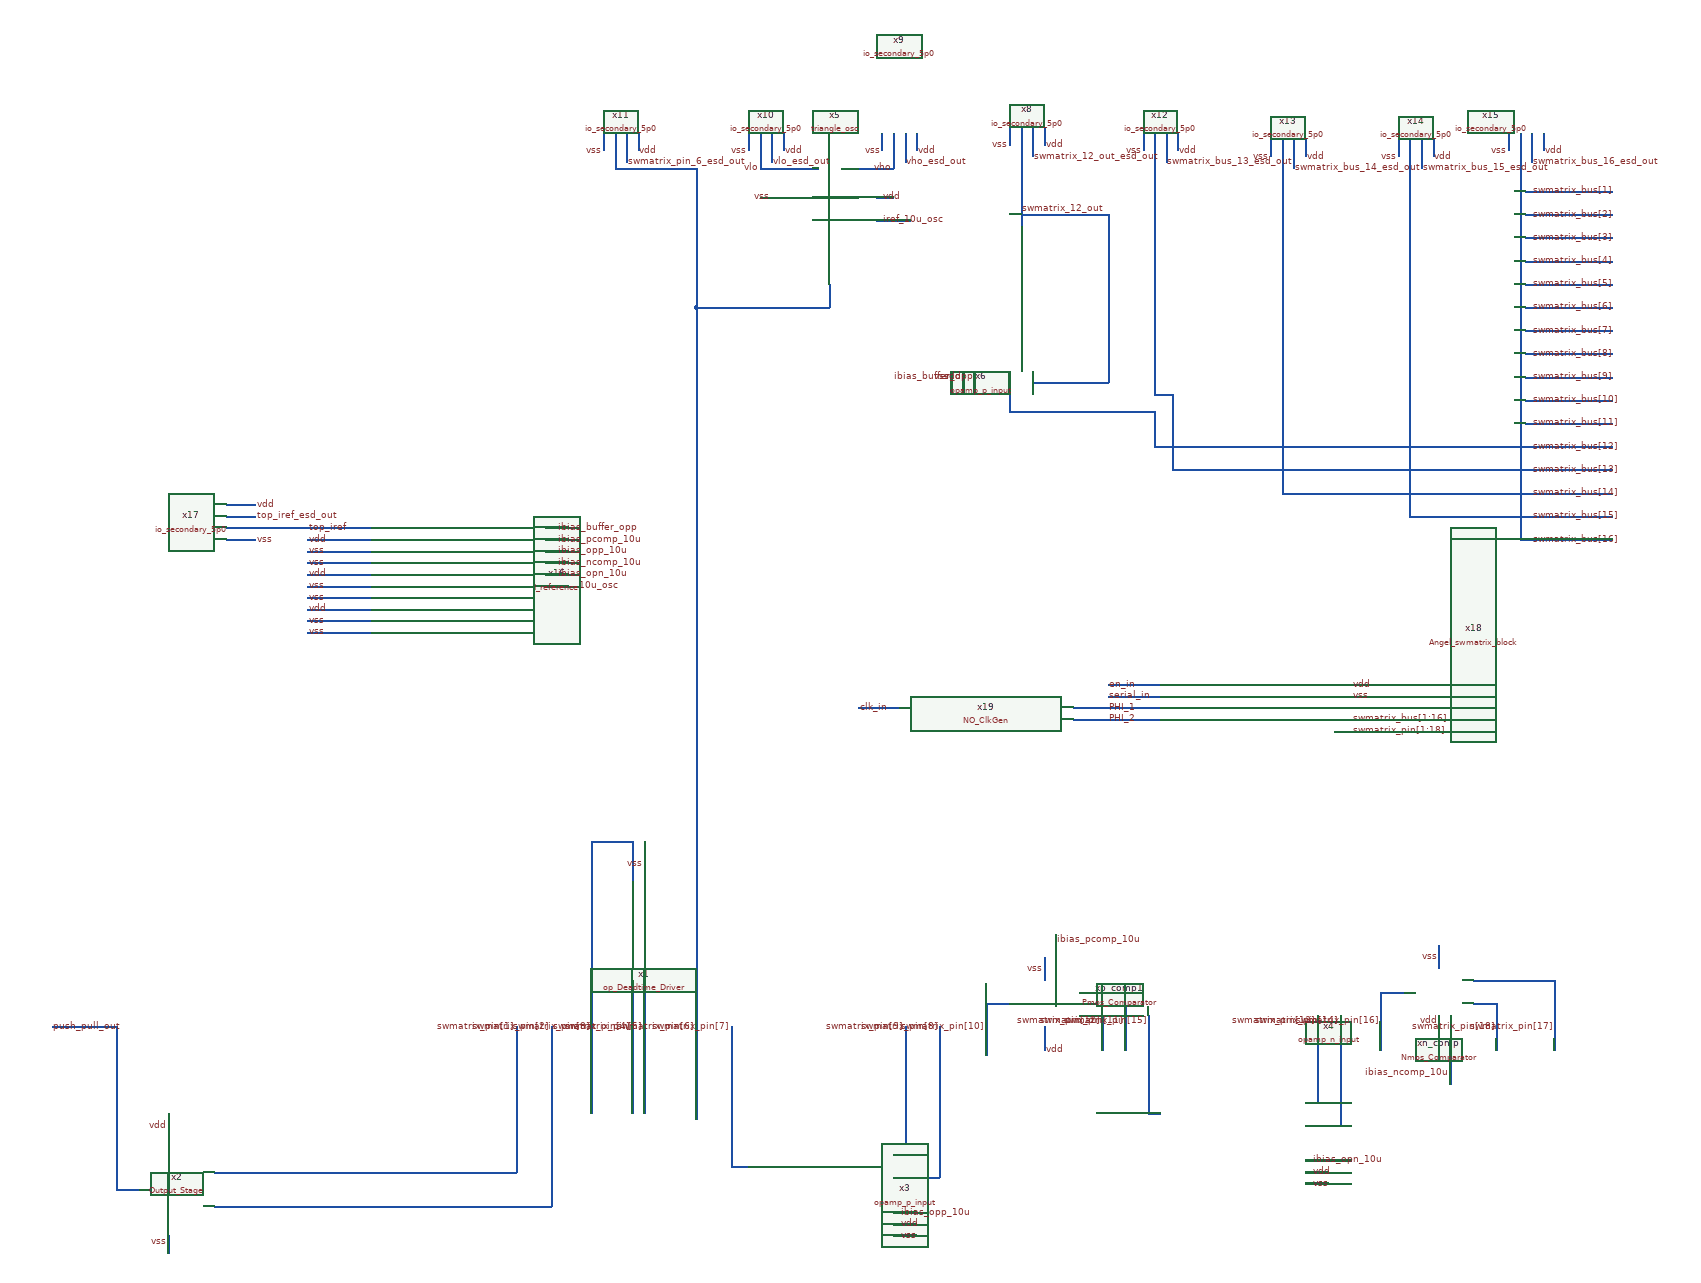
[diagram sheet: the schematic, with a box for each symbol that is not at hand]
v {xschem version=3.4.7 file_version=1.2}
G {}
K {}
V {}
S {}
E {}
N 1850 -2800 1900 -2800 {lab=vho}
N 1900 -2860 1900 -2800 {lab=vho}
N 1670 -2860 1670 -2800 {lab=vlo}
N 1420 -2860 1420 -2840 {lab=swmatrix_pin[6]}
N 2570 -2850 2570 -2820 {lab=swmatrix_bus[14]}
N 2790 -2850 2790 -2820 {lab=swmatrix_bus[15]}
N 2120 -2750 2120 -2700 {lab=swmatrix_12_out}
N 2140 -2450 2140 -2430 {lab=swmatrix_12_out}
N 2140 -2430 2270 -2430 {lab=swmatrix_12_out}
N 2270 -2710 2270 -2430 {lab=swmatrix_12_out}
N 2120 -2720 2270 -2720 {lab=swmatrix_12_out}
N 2270 -2720 2270 -2710 {lab=swmatrix_12_out}
N 650 -1170 650 -1120 {lab=vdd}
N 1670 -2750 1710 -2750 {lab=vss}
N 1870 -2750 1900 -2750 {lab=vdd}
N 1880 -2710 1930 -2710 {lab=iref_10u_osc}
N 1870 -2710 1880 -2710 {lab=iref_10u_osc}
N 1790 -2600 1790 -2560 {lab=swmatrix_pin[6]}
N 2000 -2450 2000 -2410 {lab=vss}
N 2020 -2450 2020 -2410 {lab=vdd}
N 2040 -2450 2040 -2410 {lab=ibias_buffer_opp}
N 2100 -2450 2100 -2390 {lab=swmatrix_bus[12]}
N 1900 -960 1940 -960 {lab=vss}
N 1900 -980 1940 -980 {lab=vdd}
N 1900 -1000 1940 -1000 {lab=ibias_opp_10u}
N 2610 -1050 2650 -1050 {lab=vss}
N 2610 -1070 2650 -1070 {lab=vdd}
N 2610 -1090 2650 -1090 {lab=ibias_opn_10u}
N 1900 -1100 1920 -1100 {lab=swmatrix_pin[9]}
N 1920 -1220 1920 -1100 {lab=swmatrix_pin[9]}
N 1980 -1320 1980 -1060 {lab=swmatrix_pin[8]}
N 1920 -1320 1920 -1220 {lab=swmatrix_pin[9]}
N 1620 -1320 1620 -1080 {lab=swmatrix_pin[7]}
N 2610 -1190 2630 -1190 {lab=swmatrix_pin[13]}
N 2630 -1310 2630 -1190 {lab=swmatrix_pin[13]}
N 2610 -1150 2650 -1150 {lab=swmatrix_pin[14]}
N 2650 -1090 2690 -1090 {lab=ibias_opn_10u}
N 2160 -1440 2160 -1400 {lab=vss}
N 2160 -1320 2160 -1280 {lab=vdd}
N 2160 -1440 2160 -1400 {lab=vss}
N 2160 -1320 2160 -1280 {lab=vdd}
N 2180 -1440 2180 -1400 {lab=ibias_pcomp_10u}
N 2180 -1480 2180 -1440 {lab=ibias_pcomp_10u}
N 2060 -1360 2100 -1360 {lab=swmatrix_pin[10]}
N 2220 -1340 2260 -1340 {lab=swmatrix_pin[12]}
N 2900 -1360 2940 -1360 {lab=swmatrix_pin[18]}
N 2900 -1400 3040 -1400 {lab=swmatrix_pin[17]}
N 2740 -1380 2780 -1380 {lab=swmatrix_pin[16]}
N 2840 -1460 2840 -1420 {lab=vss}
N 2840 -1460 2840 -1420 {lab=vss}
N 2860 -1340 2860 -1300 {lab=ibias_ncomp_10u}
N 1470 -1640 1470 -1570 {lab=vss}
N 1450 -1640 1450 -1570 {lab=swmatrix_pin[3]}
N 1380 -1640 1380 -1300 {lab=swmatrix_pin[3]}
N 1450 -1400 1450 -1300 {lab=swmatrix_pin[4]}
N 1670 -2800 1770 -2800 {lab=vlo}
N 1810 -2800 1850 -2800 {lab=vho}
N 1450 -1300 1450 -1170 {lab=swmatrix_pin[4]}
N 1380 -1300 1380 -1170 {lab=swmatrix_pin[3]}
N 1470 -1400 1470 -1170 {lab=swmatrix_pin[5]}
N 650 -960 650 -930 {lab=vss}
N 730 -1070 1250 -1070 {lab=swmatrix_pin[1]}
N 1250 -1170 1250 -1070 {lab=swmatrix_pin[1]}
N 730 -1010 1310 -1010 {lab=swmatrix_pin[2]}
N 1310 -1160 1310 -1010 {lab=swmatrix_pin[2]}
N 1310 -1170 1310 -1160 {lab=swmatrix_pin[2]}
N 1250 -1320 1250 -1170 {lab=swmatrix_pin[1]}
N 1310 -1320 1310 -1170 {lab=swmatrix_pin[2]}
N 2060 -1360 2060 -1300 {lab=swmatrix_pin[10]}
N 2260 -1340 2260 -1280 {lab=swmatrix_pin[12]}
N 2300 -1380 2300 -1280 {lab=swmatrix_pin[11]}
N 2740 -1380 2740 -1280 {lab=swmatrix_pin[16]}
N 2940 -1360 2940 -1280 {lab=swmatrix_pin[18]}
N 3040 -1400 3040 -1280 {lab=swmatrix_pin[17]}
N 2860 -1300 2860 -1220 {lab=ibias_ncomp_10u}
N 2670 -1310 2670 -1150 {lab=swmatrix_pin[14]}
N 2340 -1340 2340 -1170 {lab=swmatrix_pin[15]}
N 2630 -1340 2630 -1310 {lab=swmatrix_pin[13]}
N 2670 -1340 2670 -1310 {lab=swmatrix_pin[14]}
N 2840 -1340 2840 -1310 {lab=vdd}
N 1560 -2280 1560 -1160 {lab=swmatrix_pin[6]}
N 1380 -1640 1450 -1640 {lab=swmatrix_pin[3]}
N 1620 -1080 1650 -1080 {lab=swmatrix_pin[7]}
N 1900 -1060 1980 -1060 {lab=swmatrix_pin[8]}
N 2060 -1300 2060 -1270 {lab=swmatrix_pin[10]}
N 2650 -1150 2670 -1150 {lab=swmatrix_pin[14]}
N 2340 -1170 2360 -1170 {lab=swmatrix_pin[15]}
N 2220 -1380 2300 -1380 {lab=swmatrix_pin[11]}
N 2120 -2760 2120 -2750 {lab=swmatrix_12_out}
N 2990 -2760 3140 -2760 {lab=swmatrix_bus[1]}
N 2790 -2820 2790 -2720 {lab=swmatrix_bus[15]}
N 2570 -2820 2570 -2680 {lab=swmatrix_bus[14]}
N 2990 -2600 3140 -2600 {lab=swmatrix_bus[5]}
N 2990 -2560 3140 -2560 {lab=swmatrix_bus[6]}
N 2990 -2520 3140 -2520 {lab=swmatrix_bus[7]}
N 2990 -2480 3140 -2480 {lab=swmatrix_bus[8]}
N 2990 -2440 3140 -2440 {lab=swmatrix_bus[9]}
N 2990 -2400 3140 -2400 {lab=swmatrix_bus[10]}
N 2990 -2360 3140 -2360 {lab=swmatrix_bus[11]}
N 2990 -2320 3140 -2320 {lab=swmatrix_bus[12]}
N 2100 -2380 2350 -2380 {lab=swmatrix_bus[12]}
N 2100 -2390 2100 -2380 {lab=swmatrix_bus[12]}
N 2990 -2280 3140 -2280 {lab=swmatrix_bus[13]}
N 2990 -2240 3140 -2240 {lab=swmatrix_bus[14]}
N 2990 -2200 3140 -2200 {lab=swmatrix_bus[15]}
N 2990 -2160 3140 -2160 {lab=swmatrix_bus[16]}
N 1560 -2560 1560 -2280 {lab=swmatrix_pin[6]}
N 560 -1040 600 -1040 {lab=push_pull_out}
N 560 -1320 560 -1040 {lab=push_pull_out}
N 450 -1320 560 -1320 {lab=push_pull_out}
N 1560 -2560 1790 -2560 {lab=swmatrix_pin[6]}
N 1560 -2800 1560 -2560 {lab=swmatrix_pin[6]}
N 1420 -2800 1550 -2800 {lab=swmatrix_pin[6]}
N 1420 -2840 1420 -2800 {lab=swmatrix_pin[6]}
N 1550 -2800 1560 -2800 {lab=swmatrix_pin[6]}
N 2350 -2860 2350 -2640 {lab=swmatrix_bus[13]}
N 2120 -2870 2120 -2760 {lab=swmatrix_12_out}
N 3020 -2860 3020 -2830 {lab=vdd}
N 2830 -2850 2830 -2820 {lab=vdd}
N 2610 -2850 2610 -2820 {lab=vdd}
N 2390 -2860 2390 -2830 {lab=vdd}
N 2160 -2870 2160 -2840 {lab=vdd}
N 1940 -2860 1940 -2840 {lab=vdd}
N 1940 -2840 1940 -2830 {lab=vdd}
N 1710 -2860 1710 -2830 {lab=vdd}
N 1460 -2860 1460 -2830 {lab=vdd}
N 3000 -2860 3000 -2830 {lab=swmatrix_bus_16_esd_out}
N 2810 -2850 2810 -2820 {lab=swmatrix_bus_15_esd_out}
N 2590 -2850 2590 -2820 {lab=swmatrix_bus_14_esd_out}
N 2770 -2850 2770 -2820 {lab=vss}
N 2550 -2850 2550 -2820 {lab=vss}
N 2960 -2860 2960 -2830 {lab=vss}
N 2370 -2860 2370 -2830 {lab=swmatrix_bus_13_esd_out}
N 2330 -2860 2330 -2830 {lab=vss}
N 2140 -2870 2140 -2840 {lab=swmatrix_12_out_esd_out}
N 2100 -2870 2100 -2840 {lab=vss}
N 1920 -2860 1920 -2830 {lab=vho_esd_out}
N 1880 -2860 1880 -2830 {lab=vss}
N 1690 -2860 1690 -2830 {lab=vlo_esd_out}
N 1650 -2860 1650 -2830 {lab=vss}
N 1440 -2860 1440 -2830 {lab=swmatrix_pin_6_esd_out}
N 1400 -2860 1400 -2830 {lab=vss}
N 2810 -2820 2810 -2800 {lab=swmatrix_bus_15_esd_out}
N 2590 -2820 2590 -2800 {lab=swmatrix_bus_14_esd_out}
N 2370 -2830 2370 -2810 {lab=swmatrix_bus_13_esd_out}
N 2140 -2840 2140 -2820 {lab=swmatrix_12_out_esd_out}
N 1920 -2830 1920 -2810 {lab=vho_esd_out}
N 1690 -2830 1690 -2810 {lab=vlo_esd_out}
N 1440 -2830 1440 -2810 {lab=swmatrix_pin_6_esd_out}
N 2350 -2320 2990 -2320 {lab=swmatrix_bus[12]}
N 2350 -2380 2350 -2320 {lab=swmatrix_bus[12]}
N 2990 -2640 3140 -2640 {lab=swmatrix_bus[4]}
N 2350 -2640 2350 -2410 {lab=swmatrix_bus[13]}
N 2350 -2410 2380 -2410 {lab=swmatrix_bus[13]}
N 2380 -2410 2380 -2280 {lab=swmatrix_bus[13]}
N 2380 -2280 2990 -2280 {lab=swmatrix_bus[13]}
N 2570 -2680 2570 -2240 {lab=swmatrix_bus[14]}
N 2570 -2240 2990 -2240 {lab=swmatrix_bus[14]}
N 2790 -2720 2790 -2200 {lab=swmatrix_bus[15]}
N 2790 -2200 2990 -2200 {lab=swmatrix_bus[15]}
N 2990 -2720 3140 -2720 {lab=swmatrix_bus[2]}
N 2990 -2680 3140 -2680 {lab=swmatrix_bus[3]}
N 3000 -2830 3000 -2810 {lab=swmatrix_bus_16_esd_out}
N 2980 -2860 2980 -2160 {lab=swmatrix_bus[16]}
N 2980 -2160 2990 -2160 {lab=swmatrix_bus[16]}
N 960 -2180 1000 -2180 {lab=top_iref}
N 890 -2180 960 -2180 {lab=top_iref}
N 890 -2160 1000 -2160 {lab=vdd}
N 890 -2140 1000 -2140 {lab=vss}
N 890 -2120 1000 -2120 {lab=vss}
N 890 -2100 1000 -2100 {lab=vdd}
N 890 -2080 1000 -2080 {lab=vss}
N 890 -2060 1000 -2060 {lab=vss}
N 890 -2040 1000 -2040 {lab=vdd}
N 890 -2020 1000 -2020 {lab=vss}
N 890 -2000 1000 -2000 {lab=vss}
N 1300 -2180 1340 -2180 {lab=ibias_buffer_opp}
N 1300 -2160 1340 -2160 {lab=ibias_pcomp_10u}
N 1300 -2140 1340 -2140 {lab=ibias_opp_10u}
N 1300 -2120 1340 -2120 {lab=ibias_ncomp_10u}
N 1300 -2100 1340 -2100 {lab=ibias_opn_10u}
N 1300 -2080 1340 -2080 {lab=iref_10u_osc}
N 750 -2180 890 -2180 {lab=top_iref}
N 750 -2200 800 -2200 {lab=top_iref_esd_out}
N 750 -2220 800 -2220 {lab=vdd}
N 750 -2160 800 -2160 {lab=vss}
N 2660 -1870 2690 -1870 {lab=#net1}
N 2660 -1910 2690 -1910 {lab=vdd}
N 2660 -1890 2690 -1890 {lab=vss}
N 2660 -1850 2690 -1850 {lab=swmatrix_bus[1:16]}
N 2660 -1830 2690 -1830 {lab=swmatrix_pin[1:18]}
N 2210 -1870 2360 -1870 {lab=PHI_1}
N 2210 -1850 2360 -1850 {lab=PHI_2}
N 2270 -1890 2360 -1890 {lab=serial_in}
N 2270 -1910 2360 -1910 {lab=en_in}
N 1840 -1870 1910 -1870 {lab=clk_in}
C {title.sym} 70 30 0 0 {name=l1 author=", X.J. Lee, Christopher O Amankwaa"}
C {libs/core_analog/Comparator/Nmos_Comparator.sym} 2880 -1340 2 0 {name=xn_comp}
C {libs/core_analog/op_Deadtime_Driver/op_Deadtime_Driver.sym} 1460 -1420 3 1 {name=x1}
C {libs/core_analog/Output_Stage/Output_Stage.sym} 680 -1040 0 1 {name=x2}
C {libs/core_analog/opamp/opamp_p_input.sym} 1880 -1170 0 1 {name=x3}
C {libs/core_analog/opamp/opamp_n_input.sym} 2590 -1260 0 1 {name=x4}
C {libs/core_analog/oscillator/triangle_osc.sym} 1850 -2780 1 0 {name=x5}
C {libs/core_analog/opamp/opamp_p_input.sym} 2210 -2470 1 1 {name=x6}
C {lab_wire.sym} 1900 -2800 0 0 {name=p5 sig_type=std_logic lab=vho}
C {lab_wire.sym} 1670 -2800 0 0 {name=p6 sig_type=std_logic lab=vlo}
C {lab_wire.sym} 450 -1320 0 1 {name=p13 sig_type=std_logic lab=push_pull_out}
C {lab_wire.sym} 3000 -2640 0 1 {name=p56 sig_type=std_logic lab=swmatrix_bus[4]}
C {lab_wire.sym} 3000 -2600 0 1 {name=p59 sig_type=std_logic lab=swmatrix_bus[5]}
C {lab_wire.sym} 3000 -2680 0 1 {name=p60 sig_type=std_logic lab=swmatrix_bus[3]}
C {lab_wire.sym} 3000 -2720 0 1 {name=p61 sig_type=std_logic lab=swmatrix_bus[2]}
C {lab_wire.sym} 3000 -2760 0 1 {name=p62 sig_type=std_logic lab=swmatrix_bus[1]}
C {lab_wire.sym} 650 -1150 0 0 {name=p47 sig_type=std_logic lab=vdd}
C {lab_wire.sym} 1690 -2750 0 0 {name=p64 sig_type=std_logic lab=vss}
C {lab_wire.sym} 1880 -2750 0 1 {name=p65 sig_type=std_logic lab=vdd}
C {lab_wire.sym} 1880 -2710 0 1 {name=p66 sig_type=std_logic lab=iref_10u_osc}
C {lab_wire.sym} 2020 -2440 3 0 {name=p67 sig_type=std_logic lab=vdd}
C {lab_wire.sym} 2000 -2440 3 0 {name=p68 sig_type=std_logic lab=vss}
C {lab_wire.sym} 1910 -980 2 0 {name=p70 sig_type=std_logic lab=vdd}
C {lab_wire.sym} 1910 -960 2 0 {name=p71 sig_type=std_logic lab=vss}
C {lab_wire.sym} 1910 -1000 0 1 {name=p72 sig_type=std_logic lab=ibias_opp_10u}
C {lab_wire.sym} 2620 -1070 2 0 {name=p73 sig_type=std_logic lab=vdd}
C {lab_wire.sym} 2620 -1050 2 0 {name=p74 sig_type=std_logic lab=vss}
C {lab_wire.sym} 2620 -1090 0 1 {name=p75 sig_type=std_logic lab=ibias_opn_10u}
C {lab_wire.sym} 2160 -1280 0 1 {name=p76 sig_type=std_logic lab=vdd}
C {lab_wire.sym} 2180 -1470 2 0 {name=p78 sig_type=std_logic lab=ibias_pcomp_10u}
C {libs/core_analog/Comparator/Pmos_Comparator.sym} 2200 -1320 2 0 {name=xp_comp1}
C {lab_wire.sym} 2160 -1420 0 0 {name=p80 sig_type=std_logic lab=vss}
C {lab_wire.sym} 2840 -1440 0 0 {name=p82 sig_type=std_logic lab=vss}
C {lab_wire.sym} 2840 -1330 2 1 {name=p83 sig_type=std_logic lab=vdd}
C {lab_wire.sym} 2860 -1240 2 1 {name=p85 sig_type=std_logic lab=ibias_ncomp_10u}
C {lab_wire.sym} 1470 -1600 1 0 {name=p86 sig_type=std_logic lab=vss}
C {lab_wire.sym} 2630 -1330 1 1 {name=p94 sig_type=std_logic lab=swmatrix_pin[13]}
C {lab_wire.sym} 3040 -1320 1 1 {name=p101 sig_type=std_logic lab=swmatrix_pin[17]
}
C {lab_wire.sym} 650 -950 3 0 {name=p102 sig_type=std_logic lab=vss}
C {lab_wire.sym} 2120 -2730 0 1 {name=p77 sig_type=std_logic lab=swmatrix_12_out}
C {lab_wire.sym} 3000 -2560 0 1 {name=p81 sig_type=std_logic lab=swmatrix_bus[6]}
C {lab_wire.sym} 3000 -2400 0 1 {name=p84 sig_type=std_logic lab=swmatrix_bus[10]}
C {lab_wire.sym} 3000 -2360 0 1 {name=p105 sig_type=std_logic lab=swmatrix_bus[11]}
C {lab_wire.sym} 3000 -2440 0 1 {name=p106 sig_type=std_logic lab=swmatrix_bus[9]}
C {lab_wire.sym} 3000 -2480 0 1 {name=p107 sig_type=std_logic lab=swmatrix_bus[8]}
C {lab_wire.sym} 3000 -2520 0 1 {name=p108 sig_type=std_logic lab=swmatrix_bus[7]}
C {lab_wire.sym} 3000 -2320 0 1 {name=p109 sig_type=std_logic lab=swmatrix_bus[12]}
C {lab_wire.sym} 3000 -2240 0 1 {name=p110 sig_type=std_logic lab=swmatrix_bus[14]}
C {lab_wire.sym} 3000 -2200 0 1 {name=p111 sig_type=std_logic lab=swmatrix_bus[15]}
C {lab_wire.sym} 3000 -2280 0 1 {name=p112 sig_type=std_logic lab=swmatrix_bus[13]}
C {lab_wire.sym} 3000 -2160 0 1 {name=p113 sig_type=std_logic lab=swmatrix_bus[16]}
C {lab_wire.sym} 890 -2000 0 1 {name=p115 sig_type=std_logic lab=vss}
C {lab_wire.sym} 2040 -2440 3 0 {name=p119 sig_type=std_logic lab=ibias_buffer_opp}
C {lab_wire.sym} 1320 -2080 0 1 {name=p132 sig_type=std_logic lab=iref_10u_osc}
C {lab_wire.sym} 2940 -1320 1 1 {name=p100 sig_type=std_logic lab=swmatrix_pin[18]
}
C {lab_wire.sym} 2740 -1330 1 1 {name=p99 sig_type=std_logic lab=swmatrix_pin[16]
}
C {lab_wire.sym} 2670 -1330 1 1 {name=p95 sig_type=std_logic lab=swmatrix_pin[14]
}
C {lab_wire.sym} 2340 -1330 1 1 {name=p93 sig_type=std_logic lab=swmatrix_pin[15]}
C {lab_wire.sym} 2300 -1330 1 1 {name=p97 sig_type=std_logic lab=swmatrix_pin[11]}
C {lab_wire.sym} 2260 -1330 1 1 {name=p98 sig_type=std_logic lab=swmatrix_pin[12]}
C {lab_wire.sym} 2060 -1320 3 0 {name=p91 sig_type=std_logic lab=swmatrix_pin[10]}
C {lab_wire.sym} 1980 -1320 1 1 {name=p92 sig_type=std_logic lab=swmatrix_pin[8]}
C {lab_wire.sym} 1920 -1320 1 1 {name=p96 sig_type=std_logic lab=swmatrix_pin[9]}
C {lab_wire.sym} 1620 -1320 1 1 {name=p45 sig_type=std_logic lab=swmatrix_pin[7]}
C {lab_wire.sym} 1470 -1320 1 1 {name=p87 sig_type=std_logic lab=swmatrix_pin[5]}
C {lab_wire.sym} 1450 -1320 3 0 {name=p88 sig_type=std_logic lab=swmatrix_pin[4]}
C {lab_wire.sym} 1380 -1320 3 0 {name=p89 sig_type=std_logic lab=swmatrix_pin[3]}
C {lab_wire.sym} 1310 -1320 1 1 {name=p90 sig_type=std_logic lab=swmatrix_pin[2]}
C {lab_wire.sym} 1250 -1320 1 1 {name=p103 sig_type=std_logic lab=swmatrix_pin[1]}
C {lab_wire.sym} 1560 -1320 3 0 {name=p104 sig_type=std_logic lab=swmatrix_pin[6]}
C {lab_wire.sym} 2690 -1850 0 1 {name=p133 sig_type=std_logic lab=swmatrix_bus[1:16]}
C {lab_wire.sym} 2690 -1830 0 1 {name=p134 sig_type=std_logic lab=swmatrix_pin[1:18]
}
C {lab_wire.sym} 2270 -1890 0 1 {name=p135 sig_type=std_logic lab=serial_in
}
C {lab_wire.sym} 2270 -1910 0 1 {name=p136 sig_type=std_logic lab=en_in}
C {lab_wire.sym} 1840 -1870 0 1 {name=p137 sig_type=std_logic lab=clk_in
}
C {noconn.sym} 3140 -2760 0 1 {name=l24}
C {noconn.sym} 3140 -2720 0 1 {name=l25}
C {noconn.sym} 3140 -2680 0 1 {name=l26}
C {noconn.sym} 3140 -2640 0 1 {name=l27}
C {noconn.sym} 3140 -2600 0 1 {name=l28}
C {noconn.sym} 3140 -2560 0 1 {name=l29}
C {noconn.sym} 3140 -2520 0 1 {name=l30}
C {noconn.sym} 3140 -2480 0 1 {name=l31}
C {noconn.sym} 3140 -2440 0 1 {name=l32}
C {noconn.sym} 3140 -2400 0 1 {name=l33}
C {noconn.sym} 3140 -2360 0 1 {name=l34}
C {libs/core_analog/ESD/io_secondary_5p0.sym} 2130 -3020 1 0 {name=x8}
C {libs/core_analog/ESD/io_secondary_5p0.sym} 1910 -3010 1 0 {name=x9}
C {libs/core_analog/ESD/io_secondary_5p0.sym} 1680 -3010 1 0 {name=x10}
C {libs/core_analog/ESD/io_secondary_5p0.sym} 1430 -3010 1 0 {name=x11}
C {libs/core_analog/ESD/io_secondary_5p0.sym} 2360 -3010 1 0 {name=x12}
C {libs/core_analog/ESD/io_secondary_5p0.sym} 2580 -3000 1 0 {name=x13}
C {libs/core_analog/ESD/io_secondary_5p0.sym} 2800 -3000 1 0 {name=x14}
C {libs/core_analog/ESD/io_secondary_5p0.sym} 2990 -3010 1 0 {name=x15}
C {lab_wire.sym} 3020 -2830 0 1 {name=p1 sig_type=std_logic lab=vdd}
C {lab_wire.sym} 2830 -2820 0 1 {name=p2 sig_type=std_logic lab=vdd}
C {lab_wire.sym} 2610 -2820 0 1 {name=p3 sig_type=std_logic lab=vdd}
C {lab_wire.sym} 2390 -2830 0 1 {name=p4 sig_type=std_logic lab=vdd}
C {lab_wire.sym} 2160 -2840 0 1 {name=p7 sig_type=std_logic lab=vdd}
C {lab_wire.sym} 1940 -2830 0 1 {name=p8 sig_type=std_logic lab=vdd}
C {lab_wire.sym} 1710 -2830 0 1 {name=p9 sig_type=std_logic lab=vdd}
C {lab_wire.sym} 1460 -2830 0 1 {name=p10 sig_type=std_logic lab=vdd}
C {lab_wire.sym} 1400 -2830 0 0 {name=p11 sig_type=std_logic lab=vss}
C {lab_wire.sym} 1650 -2830 0 0 {name=p12 sig_type=std_logic lab=vss}
C {lab_wire.sym} 1880 -2830 0 0 {name=p14 sig_type=std_logic lab=vss}
C {lab_wire.sym} 2100 -2840 0 0 {name=p15 sig_type=std_logic lab=vss}
C {lab_wire.sym} 2330 -2830 0 0 {name=p16 sig_type=std_logic lab=vss}
C {lab_wire.sym} 2550 -2820 0 0 {name=p17 sig_type=std_logic lab=vss}
C {lab_wire.sym} 2770 -2820 0 0 {name=p18 sig_type=std_logic lab=vss}
C {lab_wire.sym} 2960 -2830 0 0 {name=p19 sig_type=std_logic lab=vss}
C {lab_wire.sym} 3000 -2810 0 1 {name=p20 sig_type=std_logic lab=swmatrix_bus_16_esd_out}
C {lab_wire.sym} 2810 -2800 0 1 {name=p21 sig_type=std_logic lab=swmatrix_bus_15_esd_out}
C {lab_wire.sym} 2590 -2800 0 1 {name=p22 sig_type=std_logic lab=swmatrix_bus_14_esd_out}
C {lab_wire.sym} 2370 -2810 0 1 {name=p23 sig_type=std_logic lab=swmatrix_bus_13_esd_out}
C {lab_wire.sym} 2140 -2820 0 1 {name=p24 sig_type=std_logic lab=swmatrix_12_out_esd_out}
C {lab_wire.sym} 1920 -2810 0 1 {name=p25 sig_type=std_logic lab=vho_esd_out}
C {lab_wire.sym} 1690 -2810 0 1 {name=p26 sig_type=std_logic lab=vlo_esd_out}
C {lab_wire.sym} 1440 -2810 0 1 {name=p27 sig_type=std_logic lab=swmatrix_pin_6_esd_out}
C {libs/core_analog/I_reference/I_reference.sym} 1150 -2090 0 0 {name=x16}
C {lab_wire.sym} 890 -2180 0 1 {name=p28 sig_type=std_logic lab=top_iref}
C {lab_wire.sym} 890 -2020 0 1 {name=p29 sig_type=std_logic lab=vss}
C {lab_wire.sym} 890 -2040 0 1 {name=p31 sig_type=std_logic lab=vdd}
C {lab_wire.sym} 890 -2060 0 1 {name=p32 sig_type=std_logic lab=vss}
C {lab_wire.sym} 890 -2080 0 1 {name=p33 sig_type=std_logic lab=vss}
C {lab_wire.sym} 890 -2100 0 1 {name=p34 sig_type=std_logic lab=vdd}
C {lab_wire.sym} 890 -2120 0 1 {name=p35 sig_type=std_logic lab=vss}
C {lab_wire.sym} 890 -2140 0 1 {name=p36 sig_type=std_logic lab=vss}
C {lab_wire.sym} 890 -2160 0 1 {name=p37 sig_type=std_logic lab=vdd}
C {lab_wire.sym} 1320 -2180 0 1 {name=p38 sig_type=std_logic lab=ibias_buffer_opp}
C {lab_wire.sym} 1320 -2160 0 1 {name=p39 sig_type=std_logic lab=ibias_pcomp_10u}
C {lab_wire.sym} 1320 -2140 0 1 {name=p41 sig_type=std_logic lab=ibias_opp_10u}
C {lab_wire.sym} 1320 -2120 0 1 {name=p42 sig_type=std_logic lab=ibias_ncomp_10u}
C {lab_wire.sym} 1320 -2100 0 1 {name=p43 sig_type=std_logic lab=ibias_opn_10u}
C {libs/core_analog/ESD/io_secondary_5p0.sym} 600 -2190 0 0 {name=x17}
C {lab_wire.sym} 800 -2200 0 1 {name=p30 sig_type=std_logic lab=top_iref_esd_out}
C {lab_wire.sym} 800 -2220 0 1 {name=p40 sig_type=std_logic lab=vdd}
C {lab_wire.sym} 800 -2160 0 1 {name=p44 sig_type=std_logic lab=vss}
C {libs/core_swmatrix/Angel_swmatrix_block.sym} 2510 -1870 0 0 {name=x18}
C {libs/core_swmatrix/NO_ClkGen.sym} 2060 -1860 0 0 {name=x19}
C {noconn.sym} 2690 -1870 2 0 {name=l2}
C {lab_wire.sym} 2690 -1910 0 1 {name=p46 sig_type=std_logic lab=vdd}
C {lab_wire.sym} 2690 -1890 0 1 {name=p48 sig_type=std_logic lab=vss}
C {lab_wire.sym} 2270 -1870 0 1 {name=p49 sig_type=std_logic lab=PHI_1}
C {lab_wire.sym} 2270 -1850 0 1 {name=p50 sig_type=std_logic lab=PHI_2}
